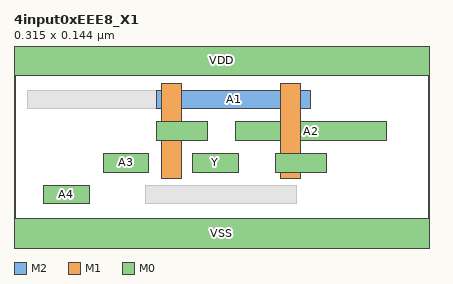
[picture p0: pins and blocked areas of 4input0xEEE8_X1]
MACRO 4input0xEEE8_X1
  CLASS CORE ;
  ORIGIN 0 0 ;
  FOREIGN 4input0xEEE8_X1 0 0 ;
  SIZE 0.3150 BY 0.1440 ;
  SYMMETRY X Y ;
  SITE coresite ;
  PIN A1
    DIRECTION INPUT ;
    USE SIGNAL ;
    PORT
      LAYER M2 ;
        RECT 0.1080 0.1010 0.2250 0.1150 ;
      LAYER M1 ;
        RECT 0.1120 0.0480 0.1270 0.1200 ;
        RECT 0.2020 0.0480 0.2170 0.1200 ;
      LAYER M0 ;
        RECT 0.1980 0.0530 0.2370 0.0670 ;
        RECT 0.1080 0.0770 0.1470 0.0910 ;
    END
  END A1
  PIN A2
    DIRECTION INPUT ;
    USE SIGNAL ;
    PORT
      LAYER M0 ;
        RECT 0.1680 0.0770 0.2820 0.0910 ;
    END
  END A2
  PIN A3
    DIRECTION INPUT ;
    USE SIGNAL ;
    PORT
      LAYER M0 ;
        RECT 0.0680 0.0530 0.1020 0.0670 ;
    END
  END A3
  PIN A4
    DIRECTION INPUT ;
    USE SIGNAL ;
    PORT
      LAYER M0 ;
        RECT 0.0220 0.0290 0.0570 0.0430 ;
    END
  END A4
  PIN Y
    DIRECTION OUTPUT ;
    USE SIGNAL ;
    PORT
      LAYER M0 ;
        RECT 0.1350 0.0530 0.1700 0.0670 ;
    END
  END Y
  PIN VDD
    DIRECTION INOUT ;
    USE POWER ;
    SHAPE ABUTMENT ;
    PORT
      LAYER M0 ;
        RECT 0.0000 0.1260 0.3150 0.1620 ;
    END
  END VDD
  PIN VSS
    DIRECTION INOUT ;
    USE GROUND ;
    SHAPE ABUTMENT ;
    PORT
      LAYER M0 ;
        RECT 0.0000 -0.0180 0.3150 0.0180 ;
    END
  END VSS
  OBS
    LAYER V1 ;
      RECT 0.1130 0.1010 0.1270 0.1150 ;
      RECT 0.2030 0.1010 0.2170 0.1150 ;
    LAYER V0 ;
      RECT 0.1130 0.0770 0.1270 0.0910 ;
      RECT 0.2030 0.0530 0.2170 0.0670 ;
    LAYER M0 ;
      RECT 0.1000 0.0290 0.2140 0.0430 ;
      RECT 0.0100 0.1010 0.2140 0.1150 ;
  END
END 4input0xEEE8_X1
